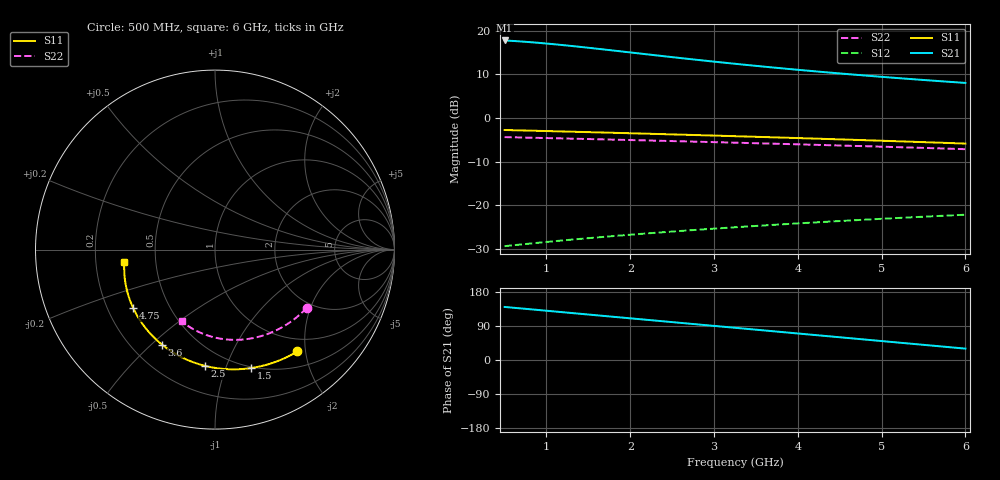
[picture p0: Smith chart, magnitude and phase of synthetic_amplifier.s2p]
! Created with skrf 2.1.0 (http://scikit-rf.org).
# GHz S MA R 50.0
!freq magS11 angS11 magS21 angS21 magS12 angS12 magS22 angS22
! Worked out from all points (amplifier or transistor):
!   111 points, 500 MHz to 6 GHz, reference 50 ohm
!   highest |S21| = 17.8 dB at 500 MHz (marker M1)
!   |S21| within 3 dB of that: start of sweep to 2.117 GHz
!   unconditionally stable (mu >= 1): 4.083 GHz to end of sweep
!   at 1.4 GHz: K = 0.59, MSG = 22.0 dB, |S12| = -27.7 dB
!   at 3.25 GHz: K = 0.84, MSG = 18.7 dB, |S12| = -25.0 dB
!   at 6 GHz: K = 1.40, MAG = 11.3 dB, |S12| = -22.2 dB
!   S11 on the Smith chart (normalised r, x): 500 MHz: 0.76, -1.85; 1.5 GHz: 0.49, -1.23; 2.5 GHz: 0.38, -0.84; 3.6 GHz: 0.32, -0.54; 4.75 GHz: 0.31, -0.29; 6 GHz: 0.33, -0.06
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0.5  0.73 -51.0  7.761 140.0  0.034 66.0  0.605 -32.5
0.7  0.722 -55.4  7.551 136.0  0.0356 64.4  0.599 -35.5
0.8  0.718 -57.6  7.428 134.0  0.0364 63.6  0.596 -37.0
0.95  0.712 -60.9  7.226 131.0  0.0376 62.4  0.5915 -39.2
1.2  0.702 -66.4  6.86 126.0  0.0396 60.4  0.584 -43.0
1.45  0.692 -71.9  6.477 121.0  0.0416 58.4  0.5765 -46.8
1.5  0.69 -73.0  6.4 120.0  0.042 58.0  0.575 -47.5
1.7  0.682 -77.4  6.096 116.0  0.0436 56.4  0.569 -50.5
1.95  0.672 -82.9  5.728 111.0  0.0456 54.4  0.5615 -54.2
2.15  0.664 -87.3  5.449 107.0  0.0472 52.8  0.5555 -57.2
2.35  0.656 -91.7  5.185 103.0  0.0488 51.2  0.5495 -60.3
2.5  0.65 -95.0  4.998 100.0  0.05 50.0  0.545 -62.5
2.85  0.636 -102.7  4.595 93.0  0.0528 47.2  0.5345 -67.8
3.25  0.62 -111.5  4.193 85.0  0.056 44.0  0.5225 -73.8
3.6  0.606 -119.2  3.885 78.0  0.0588 41.2  0.512 -79.0
3.9  0.594 -125.8  3.651 72.0  0.0612 38.8  0.503 -83.5
4.2  0.582 -132.4  3.439 66.0  0.0636 36.4  0.494 -88.0
4.45  0.572 -137.9  3.28 61.0  0.0656 34.4  0.4865 -91.8
4.75  0.56 -144.5  3.104 55.0  0.068 32.0  0.4775 -96.2
5.1  0.546 -152.2  2.921 48.0  0.0708 29.2  0.467 -101.5
5.55  0.528 -162.1  2.712 39.0  0.0744 25.6  0.4535 -108.2
6  0.51 -172.0  2.53 30.0  0.078 22.0  0.44 -115.0
